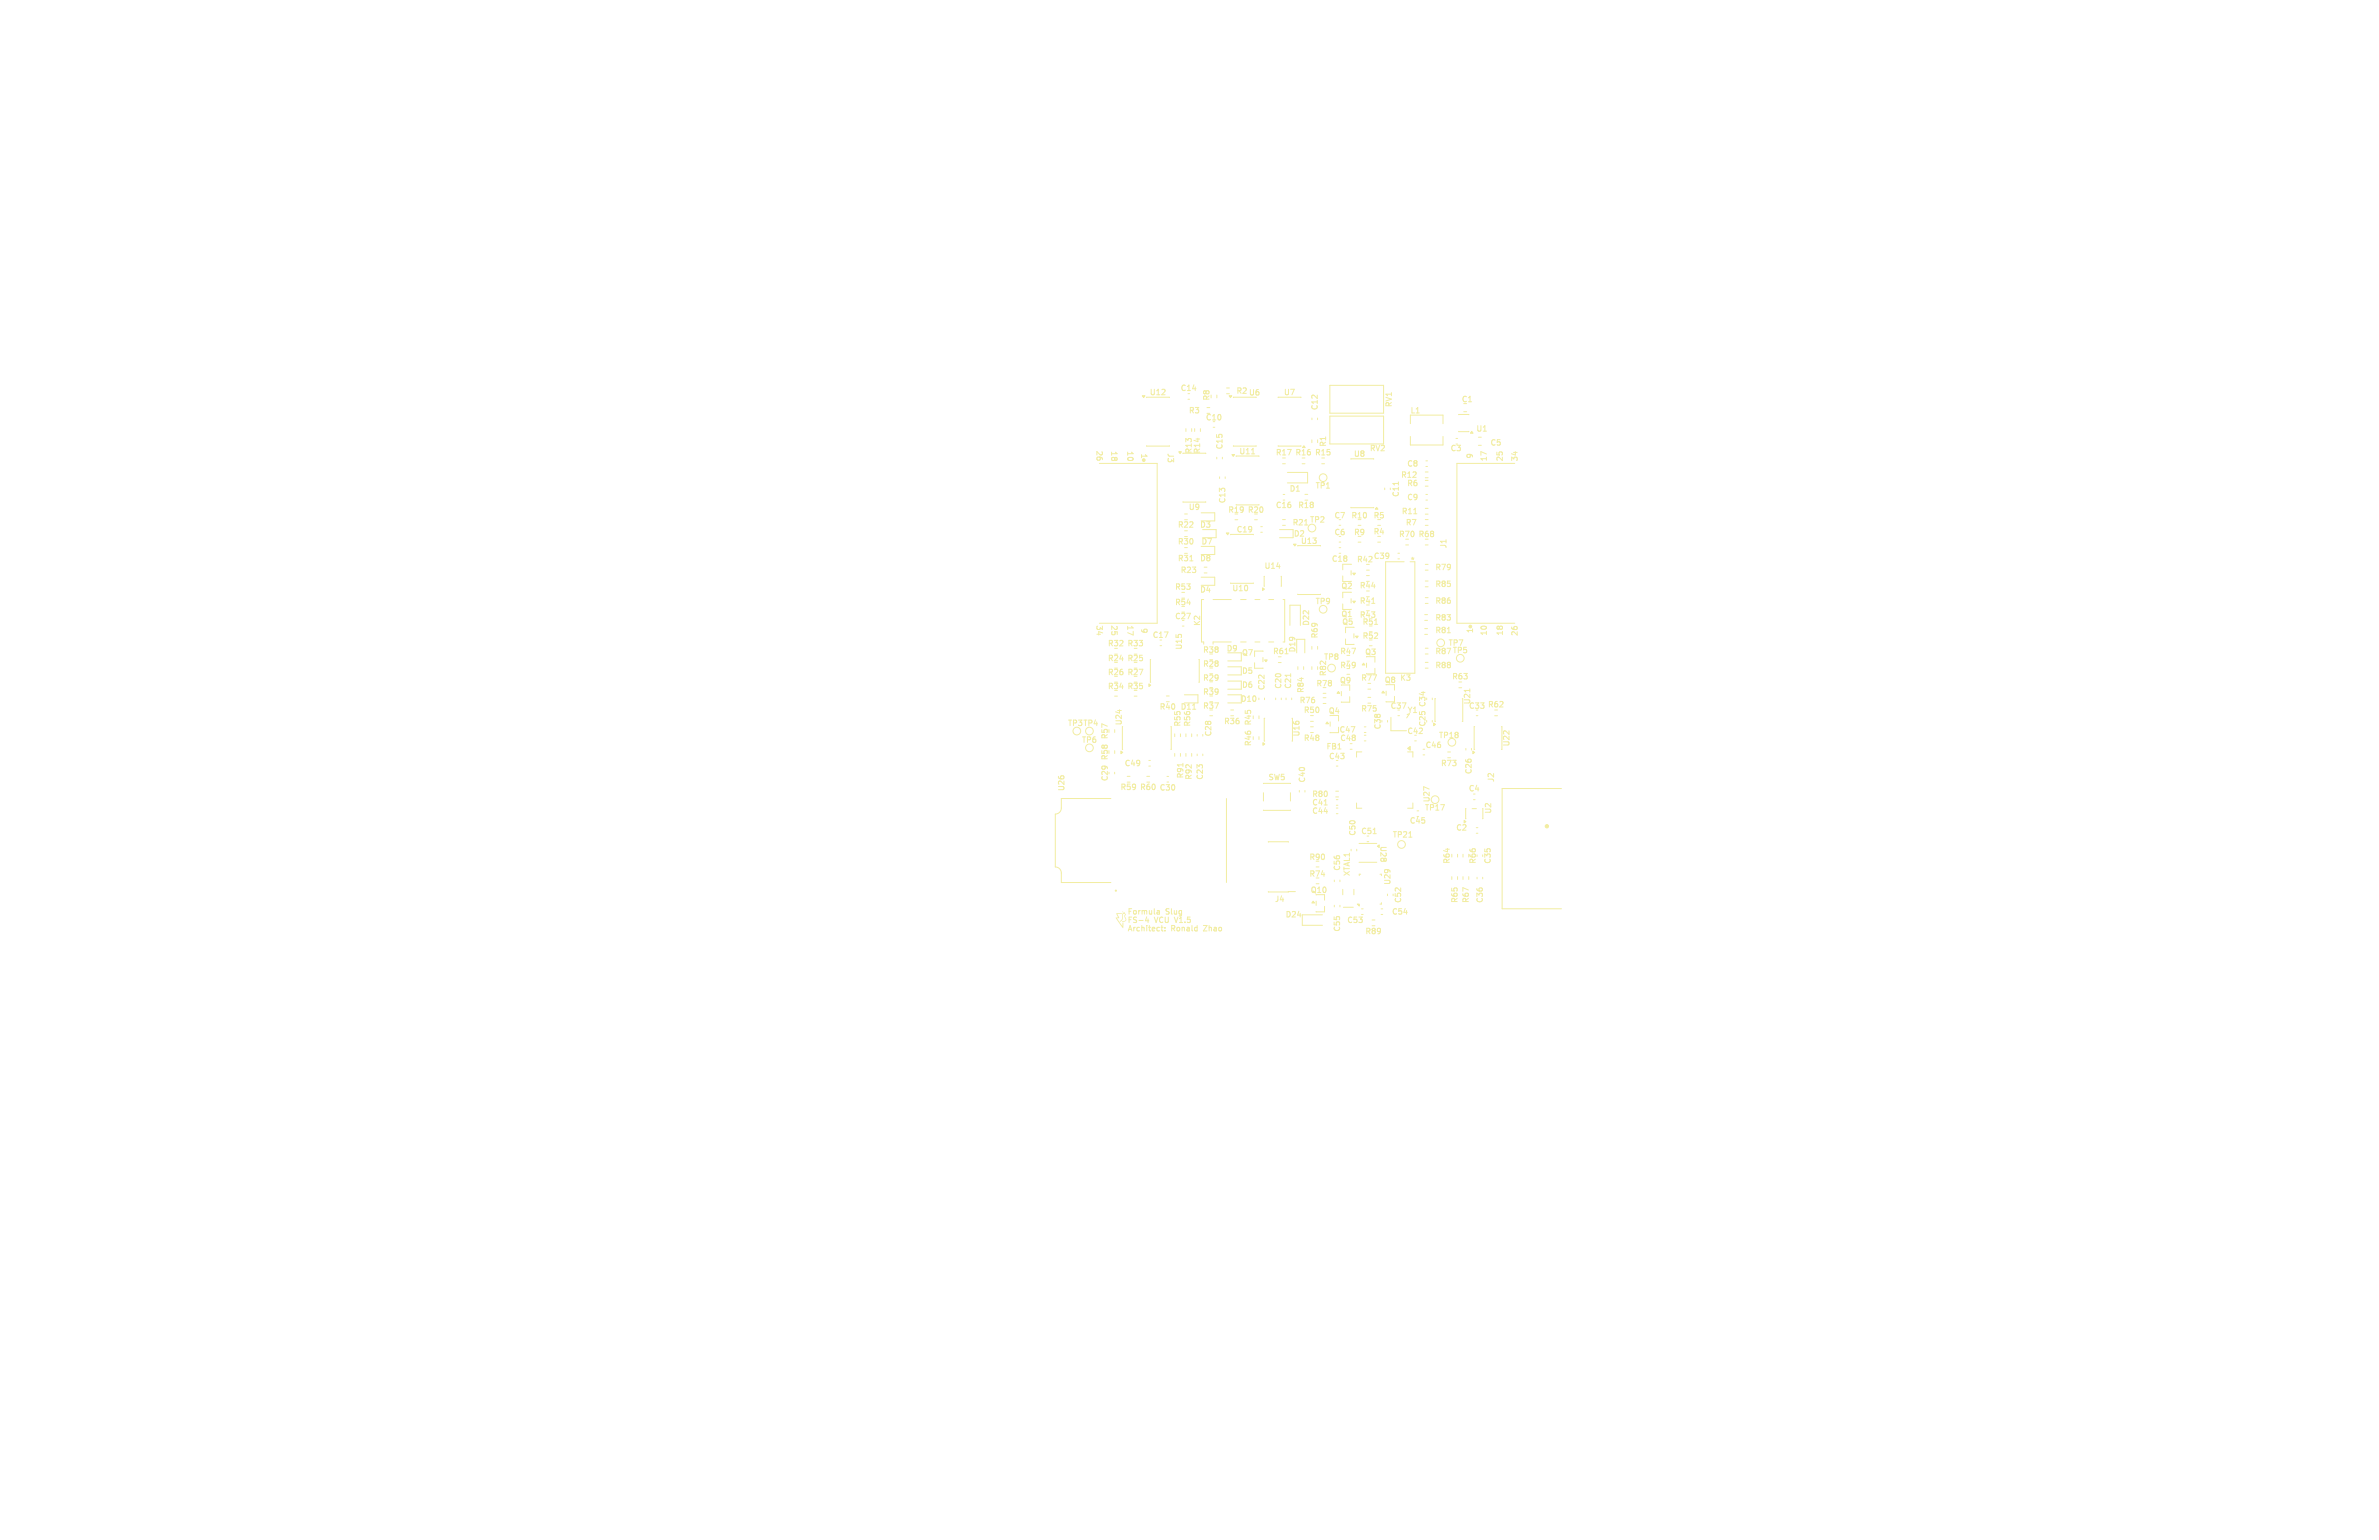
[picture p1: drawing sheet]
<svg xmlns="http://www.w3.org/2000/svg" width="432mm" height="279mm" viewBox="0 0 432 279" stroke-linecap="round" stroke-linejoin="round" font-family="sans-serif">
<defs><g id="words">
<g font-size="1.4" fill="#f2eda1">
<text x="208.6" y="71.9">U12</text>
<text x="214.2" y="71.1">C14</text>
<text x="224.3" y="71.6">R2 U6</text>
<text x="232.9" y="71.9">U7</text>
<text x="215.7" y="75.2">R3</text>
<text x="218.8" y="76.5">C10</text>
<text x="219.7" y="72.8" transform="rotate(-90 219.7 72.8)">R8</text>
<text x="239.4" y="74.5" transform="rotate(-90 239.4 74.5)">C12</text>
<text x="252.8" y="74" transform="rotate(-90 252.8 74)">RV1</text>
<text x="255.9" y="75.2">L1</text>
<text x="265.2" y="73.2">C1</text>
<text x="199" y="81.7" transform="rotate(90 199 81.7)">26</text>
<text x="201.6" y="81.8" transform="rotate(90 201.6 81.8)">18</text>
<text x="204.5" y="81.8" transform="rotate(90 204.5 81.8)">10</text>
<text x="207.1" y="82.2" transform="rotate(90 207.1 82.2)">1</text>
<text x="211.7" y="82.1" transform="rotate(90 211.7 82.1)">J3</text>
<text x="216.5" y="82.4" transform="rotate(-90 216.5 82.4)">R13</text>
<text x="218" y="82.4" transform="rotate(-90 218 82.4)">R14</text>
<text x="222.1" y="81.6" transform="rotate(-90 222.1 81.6)">C15</text>
<text x="224.8" y="82.6">U11</text>
<text x="231.5" y="82.8">R17</text>
<text x="235" y="82.8">R16</text>
<text x="238.6" y="82.8">R15</text>
<text x="240.9" y="81.2" transform="rotate(-90 240.9 81.2)">R1</text>
<text x="245.6" y="83.1">U8</text>
<text x="248.5" y="82.1">RV2</text>
<text x="263.2" y="82.1">C3</text>
<text x="267.4" y="83.3" transform="rotate(-90 267.4 83.3)">9</text>
<text x="267.9" y="78.5">U1</text>
<text x="269.9" y="83.8" transform="rotate(-90 269.9 83.8)">17</text>
<text x="270.4" y="81">C5</text>
<text x="272.8" y="83.8" transform="rotate(-90 272.8 83.8)">25</text>
<text x="275.5" y="83.8" transform="rotate(-90 275.5 83.8)">34</text>
<text x="234" y="89.4">D1</text>
<text x="238.7" y="88.8">TP1</text>
<text x="254.2" y="86.9">R12</text>
<text x="255.3" y="84.8">C8</text>
<text x="255.3" y="88.4">R6</text>
<text x="213.7" y="95.9">R22</text>
<text x="215.7" y="92.7">U9</text>
<text x="217.7" y="95.9">D3</text>
<text x="222.6" y="91.4" transform="rotate(-90 222.6 91.4)">C13</text>
<text x="222.8" y="93.2">R19</text>
<text x="226.4" y="93.2">R20</text>
<text x="231.5" y="92.4">C16</text>
<text x="234.5" y="95.5">R21</text>
<text x="235.5" y="92.4">R18</text>
<text x="237.7" y="95">TP2</text>
<text x="242.1" y="94.2">C7</text>
<text x="245.2" y="94.2">R10</text>
<text x="249.2" y="94.2">R5</text>
<text x="254.1" y="90.3" transform="rotate(-90 254.1 90.3)">C11</text>
<text x="254.3" y="93.5">R11</text>
<text x="255.1" y="95.5">R7</text>
<text x="255.3" y="90.9">C9</text>
<text x="213.7" y="99">R30</text>
<text x="218" y="99">D7</text>
<text x="224.4" y="96.8">C19</text>
<text x="234.7" y="97.5">D2</text>
<text x="236" y="98.9">U13</text>
<text x="242.1" y="97.3">C6</text>
<text x="245.7" y="97.3">R9</text>
<text x="249.2" y="97.2">R4</text>
<text x="249.2" y="101.6">C39</text>
<text x="253.8" y="97.6">R70</text>
<text x="257.4" y="97.6">R68</text>
<text x="262.7" y="99.6" transform="rotate(-90 262.7 99.6)">J1</text>
<text x="213.2" y="107.2">R53</text>
<text x="213.7" y="102">R31</text>
<text x="214.2" y="104.2">R23</text>
<text x="217.7" y="102">D8</text>
<text x="217.7" y="107.7">D4</text>
<text x="223.6" y="107.5">U10</text>
<text x="229.4" y="103.4">U14</text>
<text x="241.6" y="102.1">C18</text>
<text x="243.3" y="107.1">Q2</text>
<text x="246.2" y="102.2">R42</text>
<text x="246.7" y="106.9">R44</text>
<text x="255.9" y="102.4">*</text>
<text x="260.4" y="106.7">R85</text>
<text x="260.4" y="103.6">R79</text>
<text x="199" y="113.4" transform="rotate(90 199 113.4)">34</text>
<text x="201.7" y="113.4" transform="rotate(90 201.7 113.4)">25</text>
<text x="204.5" y="113.4" transform="rotate(90 204.5 113.4)">17</text>
<text x="207.1" y="113.9" transform="rotate(90 207.1 113.9)">9</text>
<text x="213.2" y="110">R54</text>
<text x="213.2" y="112.5">C27</text>
<text x="218" y="113.7" transform="rotate(-90 218 113.7)">K2</text>
<text x="237.8" y="113.6" transform="rotate(-90 237.8 113.6)">D22</text>
<text x="238.7" y="109.8">TP9</text>
<text x="243.3" y="112.1">Q1</text>
<text x="243.5" y="113.5">Q5</text>
<text x="246.7" y="112.3">R43</text>
<text x="246.7" y="109.7">R41</text>
<text x="247.2" y="113.5">R51</text>
<text x="260.4" y="112.8">R83</text>
<text x="260.4" y="109.7">R86</text>
<text x="201" y="117.5">R32</text>
<text x="204.5" y="117.5">R33</text>
<text x="209.1" y="115.9">C17</text>
<text x="214.7" y="118" transform="rotate(-90 214.7 118)">U15</text>
<text x="218.3" y="118.6">R38</text>
<text x="222.5" y="118.4">D9</text>
<text x="225.3" y="119.1">Q7</text>
<text x="231" y="118.9">R61</text>
<text x="235.3" y="118.5" transform="rotate(-90 235.3 118.5)">D19</text>
<text x="239.4" y="115.9" transform="rotate(-90 239.4 115.9)">R69</text>
<text x="240.2" y="119.9">TP8</text>
<text x="243.1" y="118.9">R47</text>
<text x="247.2" y="116.1">R52</text>
<text x="247.7" y="119">Q3</text>
<text x="260.4" y="115.1">R81</text>
<text x="260.4" y="118.9">R87 TP5</text>
<text x="262.8" y="117.4">TP7</text>
<text x="267.4" y="114.9" transform="rotate(-90 267.4 114.9)">1</text>
<text x="269.9" y="115.4" transform="rotate(-90 269.9 115.4)">10</text>
<text x="272.8" y="115.4" transform="rotate(-90 272.8 115.4)">18</text>
<text x="275.5" y="115.5" transform="rotate(-90 275.5 115.5)">26</text>
<text x="201" y="122.7">R26</text>
<text x="201" y="120.2">R24</text>
<text x="201" y="125.2">R34</text>
<text x="204.5" y="122.7">R27</text>
<text x="204.5" y="125.2">R35</text>
<text x="204.5" y="120.2">R25</text>
<text x="218.3" y="121.2">R28</text>
<text x="218.3" y="123.7">R29</text>
<text x="225.3" y="122.4">D5</text>
<text x="225.3" y="125">D6</text>
<text x="229.7" y="125.3" transform="rotate(-90 229.7 125.3)">C22</text>
<text x="232.8" y="125.1" transform="rotate(-90 232.8 125.1)">C20</text>
<text x="234.5" y="125.1" transform="rotate(-90 234.5 125.1)">C21</text>
<text x="236.8" y="125.8" transform="rotate(-90 236.8 125.8)">R84</text>
<text x="238.8" y="124.7">R78</text>
<text x="240.9" y="122.8" transform="rotate(-90 240.9 122.8)">R82</text>
<text x="243.1" y="124.2">Q9</text>
<text x="243.1" y="121.4">R49</text>
<text x="247" y="123.7">R77</text>
<text x="251.2" y="124.1">Q8</text>
<text x="254" y="123.7">K3</text>
<text x="260.4" y="121.4">R88</text>
<text x="263.5" y="123.5">R63</text>
<text x="193.7" y="131.9">TP3 TP4</text>
<text x="203.8" y="131.7" transform="rotate(-90 203.8 131.7)">U24</text>
<text x="210.4" y="128.9">R40</text>
<text x="214.2" y="128.9">D11</text>
<text x="214.5" y="131.9" transform="rotate(-90 214.5 131.9)">R55</text>
<text x="216.2" y="131.9" transform="rotate(-90 216.2 131.9)">R56</text>
<text x="218.3" y="128.8">R37</text>
<text x="218.3" y="126.2">R39</text>
<text x="222.1" y="131.6">R36</text>
<text x="225.1" y="127.5">D10</text>
<text x="227.3" y="131.7" transform="rotate(-90 227.3 131.7)">R45</text>
<text x="235.8" y="127.8">R76</text>
<text x="236.5" y="129.6">R50</text>
<text x="241.1" y="129.7">Q4</text>
<text x="247" y="129.3">R75</text>
<text x="252.3" y="128.8">C37</text>
<text x="255.4" y="129.6">Y1</text>
<text x="258.9" y="131.9" transform="rotate(-90 258.9 131.9)">C25</text>
<text x="258.9" y="128.4" transform="rotate(-90 258.9 128.4)">C34</text>
<text x="266.5" y="128.8">C33 R62</text>
<text x="267.1" y="127.9" transform="rotate(-90 267.1 127.9)">U21</text>
<text x="196.3" y="135">TP6</text>
<text x="201.3" y="134.2" transform="rotate(-90 201.3 134.2)">R57</text>
<text x="220.1" y="133.7" transform="rotate(-90 220.1 133.7)">C28</text>
<text x="227.3" y="135.5" transform="rotate(-90 227.3 135.5)">R46</text>
<text x="236.1" y="133.7" transform="rotate(-90 236.1 133.7)">U16</text>
<text x="236.5" y="134.6">R48</text>
<text x="240.7" y="136.2">FB1</text>
<text x="241.1" y="137.9">C43</text>
<text x="243" y="133.1">C47</text>
<text x="243.1" y="134.6">C48</text>
<text x="250.8" y="132.4" transform="rotate(-90 250.8 132.4)">C38</text>
<text x="255.3" y="133.4">C42</text>
<text x="258.6" y="135.9">C46</text>
<text x="261.1" y="134.1">TP18</text>
<text x="274.2" y="135.5" transform="rotate(-90 274.2 135.5)">U22</text>
<text x="193.4" y="143.6" transform="rotate(-90 193.4 143.6)">U26</text>
<text x="201.3" y="141.8" transform="rotate(-90 201.3 141.8)">C29</text>
<text x="201.3" y="138" transform="rotate(-90 201.3 138)">R58</text>
<text x="203.3" y="143.5">R59</text>
<text x="204" y="139.2">C49</text>
<text x="206.8" y="143.5">R60</text>
<text x="210.4" y="143.6">C30</text>
<text x="215" y="141.3" transform="rotate(-90 215 141.3)">R91</text>
<text x="216.5" y="141.6" transform="rotate(-90 216.5 141.6)">R92</text>
<text x="218.5" y="141.6" transform="rotate(-90 218.5 141.6)">C23</text>
<text x="230.1" y="141.7">SW5</text>
<text x="237.1" y="142.1" transform="rotate(-90 237.1 142.1)">C40</text>
<text x="261.4" y="139.2">R73</text>
<text x="266.5" y="143.8">C4</text>
<text x="267.3" y="140.6" transform="rotate(-90 267.3 140.6)">C26</text>
<text x="271.4" y="142" transform="rotate(-90 271.4 142)">J2</text>
<text x="238.1" y="146.3">C41</text>
<text x="238.1" y="144.8">R80</text>
<text x="238.1" y="147.8">C44</text>
<text x="255.8" y="149.6">C45</text>
<text x="258.5" y="147.3">TP17</text>
<text x="259.7" y="145.7" transform="rotate(-90 259.7 145.7)">U27</text>
<text x="270.9" y="147.7" transform="rotate(-90 270.9 147.7)">U2</text>
<text x="246.2" y="151.7" transform="rotate(-90 246.2 151.7)">C50</text>
<text x="247" y="151.5">C51</text>
<text x="250.3" y="153.4" transform="rotate(90 250.3 153.4)">U28</text>
<text x="252.7" y="152.2">TP21</text>
<text x="264.2" y="150.9">C2</text>
<text x="237.6" y="159.3">R74</text>
<text x="237.6" y="156.2">R90</text>
<text x="243.4" y="158.1" transform="rotate(-90 243.4 158.1)">C56</text>
<text x="245.2" y="159.1" transform="rotate(-90 245.2 159.1)">XTAL1</text>
<text x="252.6" y="160.7" transform="rotate(-90 252.6 160.7)">U29</text>
<text x="263.3" y="156.8" transform="rotate(-90 263.3 156.8)">R64</text>
<text x="268.1" y="156.8" transform="rotate(-90 268.1 156.8)">R66</text>
<text x="270.8" y="156.8" transform="rotate(-90 270.8 156.8)">C35</text>
<text x="204.6" y="167.6">FS-4</text>
<text x="204.6" y="166.1">Formula</text>
<text x="209.6" y="167.6">VCU</text>
<text x="211.6" y="166.1">Slug</text>
<text x="213.5" y="167.6">V1.5</text>
<text x="231.3" y="163.8">J4</text>
<text x="233.2" y="166.6">D24</text>
<text x="237.8" y="162.2">Q10</text>
<text x="244.4" y="167.7">C53</text>
<text x="252.5" y="166.1">C54</text>
<text x="254.5" y="163.9" transform="rotate(-90 254.5 163.9)">C52</text>
<text x="264.8" y="163.9" transform="rotate(-90 264.8 163.9)">R65</text>
<text x="266.8" y="163.9" transform="rotate(-90 266.8 163.9)">R67</text>
<text x="269.3" y="163.9" transform="rotate(-90 269.3 163.9)">C36</text>
<text x="204.6" y="169.2">Architect:</text>
<text x="212.6" y="169.2">Ronald</text>
<text x="218.7" y="169.2">Zhao</text>
<text x="243.4" y="169.1" transform="rotate(-90 243.4 169.1)">C55</text>
<text x="247.7" y="169.7">R89</text>
</g>
</g></defs>
<g fill="none" stroke="#f2eda1" stroke-width=".18">
<path d="M215.6 72.4h.3M216.8 77.8v.5M217.9 77.8v.5M228 72.1h-4.1M232 72.1h4.1M256 76.9v-1.6h5.9v1.6M256 79.2v1.5h5.9v-1.5M264.3 79.5h.3M265.7 74.7h.5M218 99.1h2.5v1.5h-2.5M220.8 83v.3M221.4 86.5v.3"/>
<path d="M221.9 83v.3M222.4 86.5v.3M223.4 97h4.1M223.9 80.9h4.1M224.2 94.3h.5M227.2 82.3h.5M227.7 94.3h.5M232 80.9h4.1M232.2 97.6h2.5M232.2 96.1h2.5M232.8 94.3h.5M232.8 95.3h.5"/>
<path d="M232.9 89.7h.3M232.9 90.7h.3M233.7 85.7h3.6v1.9h-3.6M236.8 95.2h.6M250.1 98.4h.5M253.8 87.4v.6M256.6 93.2h.6M258.7 92.2h.5M258.7 93.3h.5M216 101.8h.5M223.4 105.8h4.1M229.2 118.2l-1.5-.1v1"/>
<path d="M229.2 119.3v.8M233.2 118.6h.6M238.1 117.3v.5M239.2 117.3v.5M244.2 113.8v1M244.2 115.9v1h1.5M245.7 115v.8M249 109.5h.5M249.5 113.3h.6M254.9 101.9h-3.4v20.2h5.3v-20.2M262.7 114.8h.6M213.2 133.1v.6"/>
<path d="M214.3 133.1v.6M214.7 138.5v.6M215.2 136.7v.5M216.3 136.7v.5M216.5 128.7h.5M222.8 122.4h2.5M222.8 121h2.5M223.4 128.8h.5M223.4 129.9h.5M227.7 120.2v1h1.5M228.5 129.9v.5M229.6 130.3h-.1v4.1h.1"/>
<path d="M231.5 126.6v.3M232.6 126.6v.3M233.4 126.6v.3M234.3 122.2v.6M234.4 126.6v.3M234.5 130.3h.1v4.1h-.1M238.1 121v.5M239.2 121v.5M241.4 131v.8M241.4 132.9h1.5M242.9 129.8v1M243.5 125.4v.8"/>
<path d="M244.5 122.3h.5M245 126.4v1l-1.5-.1M245 124.3v1M247.2 136.4h-1v1M248.3 126.5h.5M248.3 127.6h.5M253.7 129.8h.3M255.5 136.4h.9v1M255.8 129.5l-.5 .7M256.8 134.4h.3M260 126.6v.3M264.8 124.8h.5"/>
<path d="M266.8 125v.6M201.6 144.9h-9v1.7a1.09 1.09 0 0 1-1.1 1.1v9.6a1.09 1.09 0 0 1 1.1 1.1v1.7h9M208.2 140.9h.5M208.2 141.9h.5M222.6 144.9v15.2M240.3 146h.6M242.2 159.7v.3M242.5 145.1h.3M242.5 146.1h.3M243.2 159.7v.3M246.2 145.7v.9h1M246.7 153h3.2"/>
<path d="M246.7 156.4h3.2M249.2 151.3h.6M255.7 151.9h.6M256.4 145.7v.9h-.9M257.2 147.1h.3M264.6 155v.5M266.1 146.7v1.8M267.2 146.7h.8M267.9 150.2h.3M267.9 151.2h.3M269.1 146.7v1.8M208.1 166.3l-.2 .7h.6"/>
<path d="M208.4 166.7v.7M211.4 168.8v.1M211.4 168.3v.1M242.2 164.2v.3M243.2 164.2v.3M247.1 164.9h.3M247.1 165.9h.3"/>
<circle cx="240.2" cy="86.7" r=".7"/>
<circle cx="254.4" cy="153.2" r=".7"/>
<circle cx="260.5" cy="145.1" r=".7"/>
</g>
<g fill="#f2eda1" stroke="#f2eda1" stroke-width=".18">
<path d="M222.6 96.7h.5l-.3 .3z"/>
<path d="M236.7 80.9l.2 .3h-.5z"/>
<path d="M229.5 119.7h.5l-.2 .4z"/>
<path d="M246 115.4h.5l-.2 .3z"/>
<path d="M229.2 134.7l.4 .3-.4 .2z"/>
<path d="M255.5 135.8l.5-.4v.7z"/>
<path d="M242.9 125.5l.3 .3h-.5z"/>
<path d="M240.9 131l.2 .3h-.5z"/>
<path d="M265.7 148.8l.4 .3-.4 .2z"/>
<path d="M223.1 71.8h.5l-.3 .3z"/>
</g>
<circle cx="202.5" cy="161.6" r=".1" fill="none" stroke="#f2eda1" stroke-width=".2"/>
<g fill="#f2eda1">
<path d="M202.6 165.7h1.1l-.1 .1h-.8l.3 .8h-.4l1 1.4 .1-.5 .1-.1v1l-1.4-1.9 .4-.1z"/>
<path d="M203.7 165.4h.1l.2 .2 .2-.1v.2a.34 .34 0 0 1 0 .6 .56 .56 0 0 1 .2 .7 .56 .56 0 0 1-.7 .2v-.1a.37 .37 0 0 0 .5 0 .37 .37 0 0 0 .1-.4 .65 .65 0 0 1-.1-.8l-.3-.1-.1 .4a.79 .79 0 0 1-.6 1 1.18 1.18 0 0 0 .5-1.3l.1-.2z"/>
</g>
<g fill="none" stroke="#f2eda1" stroke-width=".18">
<path d="M208.1 72.1h4.1M215.2 77.8v.5M216.3 77.8v.5M219.1 73.9h.5M220.2 77.5h.3M220.9 71.7v.5M222.6 70.4h.5M222.6 71.4h.5M238.1 79.8v.5M238.1 75.8v.3M239.1 75.8v.3M239.2 79.8v.5"/>
<path d="M241.4 75.5h9.7v5h-9.7zM241.4 69.9h9.7v5.1h-9.7zM264.8 75.2h1.8M264.8 78.3h1.8M268.3 79.3h.6M199.5 84.1h10.5v29h-10.5M208.1 80.9h4.1M214.7 82.3h4.1M214.7 91h4.1M215 93.3h.5M215 94.3h.5M215 97.3h.5"/>
<path d="M218 93h2.5v1.5h-2.5M218.3 96.1h2.4v1.5h-2.4M224.4 82.8h4.1M224.4 91.5h4.1M228.8 95.6h.3M228.8 96.6h.3M232.8 84.1h.5M235.6 99.1h4.1M236.3 84.1h.6M236.9 89.7h.5M236.9 90.7h.5M239.9 84.1h.5"/>
<path d="M243.1 95.3h.2M243.1 98.3h.2M243.1 99.4h.2M245.2 83.3h4.1M245.2 92h4.1M246.5 95.3h.5M246.5 98.4h.5M250.1 95.3h.5M251.3 88.5v.3M252.3 88.5v.3M255.1 98.9h.5M258.7 98.9h.5"/>
<path d="M258.7 95.3h.5M258.7 85.6h.5M258.7 86.7h.5M258.7 94.3h.5M258.7 87.2h.5M258.7 88.2h.5M258.8 89.7h.3M258.8 90.7h.3M258.8 83.6h.3M258.8 84.6h.3M268.3 80.8h.6M274.9 84.1h-10.5v29h10.5"/>
<path d="M208.9 119.7v4.1M210.5 117.1h.3M214.6 113.6h.3M215 100.4h.5M217.6 119.7v4.1M218 104.7h2.5v1.5h-2.5M218.5 108.8h-.4v7.7h.4v.4M218.6 102.9h.5M218.6 103.9h.5M220.2 108.8h3.3M222.8 118.4h2.5v1.5h-2.5M223.5 116.5h-3.3v.4"/>
<path d="M225.2 108.8h1M225.2 116.5h1M227.8 108.8h.9M227.8 116.5h.9M229.5 104.6v1.7M230.3 108.8h.9M230.3 116.5h.9M232.5 104.6v1.7M232.9 108.8h.3v7.7h-.3M234.1 113.5v-3.7h1.9v3.7M235.4 118.5v-2.5h1.4v2.5M235.6 107.8h4.1"/>
<path d="M243.1 100.4h.2M243.7 104.5v1l1.5-.1M243.7 109.6v1l1.5-.1M243.7 107.5v1M245.2 102.4h-1.5v1M245.2 103.5v.8M245.2 108.6v.8M248 103.4h.5M248 104.4h.5M248.5 117.2h.5M249.6 119.1v1M253.7 100.4h.3"/>
<path d="M253.7 101.4h.3M258.6 114.1h.5M258.6 115.1h.5M258.6 111.5h.5M258.6 112.6h.5M258.7 105.4h.5M258.7 106.5h.5M258.7 117.6h.5M258.7 118.7h.5M258.7 102.4h.5M258.7 103.4h.5M258.7 108.4h.5"/>
<path d="M258.7 109.5h.5M202.3 126.3h.5M202.3 132.4v.5M202.3 136.2v.5M203.7 131.8l.1 4.2M205.9 126.3h.5M208.5 138h.3M208.5 139h.3M211.7 127.3h.5M211.7 126.3h.5M212.5 131.8v4.2M213.2 136.7v.5"/>
<path d="M214.3 136.7v.5M215 126.1h2.4v1.4h-2.4M215.2 133.1v.6M216.3 133.1v.6M217.3 133.3v.2M217.3 136.8v.3M218.3 133.3v.2M218.3 136.8v.3M219.6 129.9h.5M219.6 124.7h.5M222.8 125h2.5M222.8 123.6h2.5"/>
<path d="M222.8 127.5h2.5M222.8 126.1h2.5M228.5 126.6v.3M228.5 133.7v.5M229.5 126.6v.3M232 120.2h.5M235.6 121v.5M236.6 121v.5M237.9 131.9h.5M237.9 132.9h.5M237.9 130.9h.5M240.2 126.6h.5"/>
<path d="M240.2 127.6h.5M240.2 125.8h.5M242.5 139h.3M245.1 135.9h.3M247.6 131.9h.3M247.6 133.4h.3M247.6 134.4h.3M247.6 132.9h.3M248 120.3v.8M248 122.2v.1M248.3 125h.5M249.6 121.3v1"/>
<path d="M251.6 125.4v.8M251.8 130.7v.3M252.5 130.2v2.4h2.8M253.1 126.3v1h-1.5M253.1 124.2v1M258.3 137h.3M258.7 120.2h.5M258.7 121.2h.5M260 130.7v.3M260.6 126.8h-.1v4.1h.1M262.8 136.4h.5M262.8 137.5h.5"/>
<path d="M265.4 126.8h.1v4.1h-.1M266.1 135.8v.3M267.1 135.8v.3M267.7 131.8h-.1v4.2h.1M267.9 129.8h.3M271.3 129.9h.5M272.5 131.8h.1v4.2h-.1M202.3 140.1v.3M204.6 140.9h.5M204.6 141.9h.5M211.8 140.9h.3M211.8 141.9h.3"/>
<path d="M229.3 142.2h4.9M229.3 143.8v1.5M229.3 147h4.9M230.2 152.8h3.6M234.2 143.8v1.5M235.8 143.4v.3M236.9 143.4v.3M238.9 157.3h.5M242.4 143.5h.5M242.4 144.6h.5M242.5 146.6h.3M242.5 147.6h.3"/>
<path d="M245.2 154.1v.3M246.3 154.1v.3M247 158.6h-.3v.3M248.1 152.7h.3M250.5 158.6h.2v.3M263.5 159.1v.5M264.6 159.1v.5M265.5 155v.5M265.5 159.1v.5M266.6 159.1v.5M267.4 145.1h.3M268.1 159.2v.3"/>
<path d="M269.1 155.1v.3M269.1 159.2v.3M283.4 143.1h-10.8v21.8h10.8M230.2 161.8h4.9M238.9 160.3h.5M238.9 163.5v.8M240 166h-3.6v1.9h3.6M240.4 164.4v1h-1.5M240.4 162.3v1M243.7 161.4v.9M243.8 164.6h1.8M245.7 161.4v.9"/>
<path d="M249 166.9h.6M249 168h.6M250.7 164.9h.3M250.7 165.9h.3M250.7 163.8v.2h-.2M251.8 162.2v.3M252.9 162.2v.3"/>
<circle cx="238.1" cy="95.8" r=".7"/>
<circle cx="240.2" cy="110.5" r=".7"/>
<circle cx="261.5" cy="116.6" r=".7"/>
<circle cx="265" cy="119.4" r=".7"/>
<circle cx="195.5" cy="132.6" r=".7"/>
<circle cx="197.7" cy="132.6" r=".7"/>
<circle cx="197.7" cy="135.7" r=".7"/>
<circle cx="241.7" cy="121.2" r=".7"/>
<circle cx="263.5" cy="134.7" r=".7"/>
</g>
<g fill="#f2eda1" stroke="#f2eda1" stroke-width=".18">
<path d="M208.5 124.1l.4 .2-.4 .3z"/>
<path d="M267.1 78.3l.3 .3h-.5z"/>
<path d="M229.2 106.6l.3 .3-.3 .2z"/>
<path d="M234.8 98.7h.5l-.3 .4z"/>
<path d="M238.3 163.5l.3 .3h-.5z"/>
<path d="M245.5 104h.5l-.2 .3z"/>
<path d="M267.3 136.3l.4 .2-.4 .2z"/>
<path d="M223.6 82.5h.5l-.3 .3z"/>
<path d="M245.5 109.1h.5l-.2 .3z"/>
<path d="M247.5 120.3l.2 .3h-.4z"/>
<path d="M249.9 92l.2 .4h-.5z"/>
<path d="M207.3 71.8h.5l-.2 .3z"/>
<path d="M251 125.4l.3 .3h-.5z"/>
<path d="M260.2 131.2l.3 .2-.3 .3z"/>
<path d="M213.9 82h.5l-.2 .3z"/>
<path d="M203.5 136.3l.3 .2-.3 .2z"/>
<path d="M246.4 164h.3v.4z"/>
<circle cx="207.6" cy="83.5" r=".25"/>
<circle cx="266.9" cy="113.7" r=".25"/>
<circle cx="280.8" cy="149.9" r=".3"/>
</g>
<use href="#words"/>
</svg>
